########################################################################
# Hand-written macro LEF for FRIDA analog primitive cells
#
# These are simplified physical abstracts for the sg13_lv_nmos and
# sg13_lv_pmos devices as generated by flow/mosfet/primitive.py with
# default MosfetParams (nf=4, w=1, l=1, vth=LOW, source_tie=OFF, pr=2).
#
# Cell size: 3.020 x 3.060 um (from KLayout bbox in dbu with dbu=0.001)
#
# Pin positions are derived from the PIN1-layer boxes emitted by the
# mosfet generator:
#   vss:  (0,0)       -> (0.320, 0.320)     bottom-left power rail
#   vdd:  (0,2.740)   -> (0.320, 3.060)     top-left power rail
#   gate: (0,1.450)   -> (0.320, 1.610)     left-side gate access
#   drain:(2.700,0.570)-> (3.020, 0.730)    right-side drain/source pad
#
# Obstruction covers the full cell on Metal1 (the only routed layer
# inside the primitive).
#
# NOTE: This is a temporary hand-written file for verifying that
# OpenROAD can read our design. The real flow will generate this
# from vlsir.raw via Layout21's LefExporter.
########################################################################

VERSION 5.7 ;
BUSBITCHARS "[]" ;
DIVIDERCHAR "/" ;

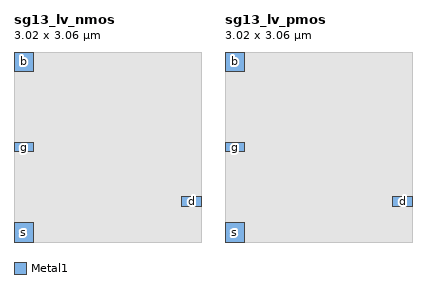
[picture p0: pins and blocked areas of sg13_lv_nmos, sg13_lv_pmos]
MACRO sg13_lv_nmos
  CLASS BLOCK ;
  ORIGIN 0 0 ;
  FOREIGN sg13_lv_nmos 0 0 ;
  SIZE 3.020 BY 3.060 ;
  SYMMETRY X Y ;

  PIN d
    DIRECTION INOUT ;
    USE SIGNAL ;
    PORT
      LAYER Metal1 ;
        RECT 2.700 0.570 3.020 0.730 ;
    END
  END d

  PIN g
    DIRECTION INPUT ;
    USE SIGNAL ;
    PORT
      LAYER Metal1 ;
        RECT 0.000 1.450 0.320 1.610 ;
    END
  END g

  PIN s
    DIRECTION INOUT ;
    USE SIGNAL ;
    PORT
      LAYER Metal1 ;
        RECT 0.000 0.000 0.320 0.320 ;
    END
  END s

  PIN b
    DIRECTION INOUT ;
    USE SIGNAL ;
    PORT
      LAYER Metal1 ;
        RECT 0.000 2.740 0.320 3.060 ;
    END
  END b

  OBS
    LAYER Metal1 ;
      RECT 0.000 0.000 3.020 3.060 ;
  END

END sg13_lv_nmos

MACRO sg13_lv_pmos
  CLASS BLOCK ;
  ORIGIN 0 0 ;
  FOREIGN sg13_lv_pmos 0 0 ;
  SIZE 3.020 BY 3.060 ;
  SYMMETRY X Y ;

  PIN d
    DIRECTION INOUT ;
    USE SIGNAL ;
    PORT
      LAYER Metal1 ;
        RECT 2.700 0.570 3.020 0.730 ;
    END
  END d

  PIN g
    DIRECTION INPUT ;
    USE SIGNAL ;
    PORT
      LAYER Metal1 ;
        RECT 0.000 1.450 0.320 1.610 ;
    END
  END g

  PIN s
    DIRECTION INOUT ;
    USE SIGNAL ;
    PORT
      LAYER Metal1 ;
        RECT 0.000 0.000 0.320 0.320 ;
    END
  END s

  PIN b
    DIRECTION INOUT ;
    USE SIGNAL ;
    PORT
      LAYER Metal1 ;
        RECT 0.000 2.740 0.320 3.060 ;
    END
  END b

  OBS
    LAYER Metal1 ;
      RECT 0.000 0.000 3.020 3.060 ;
  END

END sg13_lv_pmos

END LIBRARY
